VERSION 5.7 ;
  NOWIREEXTENSIONATPIN ON ;
  DIVIDERCHAR "/" ;
  BUSBITCHARS "[]" ;
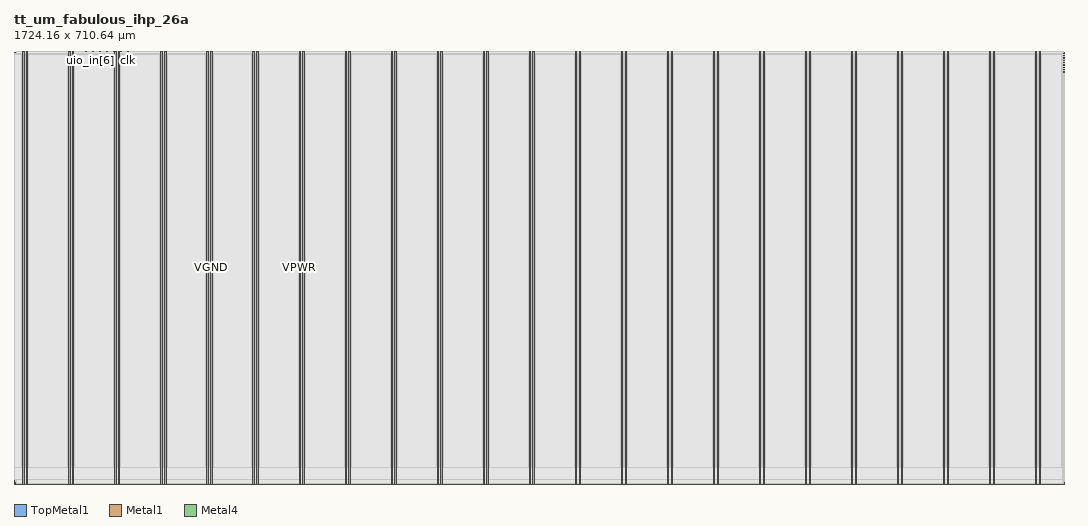
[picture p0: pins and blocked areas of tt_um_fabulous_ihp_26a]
MACRO tt_um_fabulous_ihp_26a
  CLASS BLOCK ;
  FOREIGN tt_um_fabulous_ihp_26a ;
  ORIGIN 0.000 0.000 ;
  SIZE 1724.160 BY 710.640 ;
  PIN VGND
    DIRECTION INOUT ;
    USE GROUND ;
    PORT
      LAYER TopMetal1 ;
        RECT 20.620 0.000 22.820 710.640 ;
    END
    PORT
      LAYER TopMetal1 ;
        RECT 96.220 0.000 98.420 710.640 ;
    END
    PORT
      LAYER TopMetal1 ;
        RECT 171.820 0.000 174.020 710.640 ;
    END
    PORT
      LAYER TopMetal1 ;
        RECT 247.420 0.000 249.620 710.640 ;
    END
    PORT
      LAYER TopMetal1 ;
        RECT 323.020 0.000 325.220 710.640 ;
    END
    PORT
      LAYER TopMetal1 ;
        RECT 398.620 0.000 400.820 710.640 ;
    END
    PORT
      LAYER TopMetal1 ;
        RECT 474.220 0.000 476.420 710.640 ;
    END
    PORT
      LAYER TopMetal1 ;
        RECT 549.820 0.000 552.020 710.640 ;
    END
    PORT
      LAYER TopMetal1 ;
        RECT 625.420 0.000 627.620 710.640 ;
    END
    PORT
      LAYER TopMetal1 ;
        RECT 701.020 0.000 703.220 710.640 ;
    END
    PORT
      LAYER TopMetal1 ;
        RECT 776.620 0.000 778.820 710.640 ;
    END
    PORT
      LAYER TopMetal1 ;
        RECT 852.220 0.000 854.420 710.640 ;
    END
    PORT
      LAYER TopMetal1 ;
        RECT 927.820 0.000 930.020 710.640 ;
    END
    PORT
      LAYER TopMetal1 ;
        RECT 1003.420 0.000 1005.620 710.640 ;
    END
    PORT
      LAYER TopMetal1 ;
        RECT 1079.020 0.000 1081.220 710.640 ;
    END
    PORT
      LAYER TopMetal1 ;
        RECT 1154.620 0.000 1156.820 710.640 ;
    END
    PORT
      LAYER TopMetal1 ;
        RECT 1230.220 0.000 1232.420 710.640 ;
    END
    PORT
      LAYER TopMetal1 ;
        RECT 1305.820 0.000 1308.020 710.640 ;
    END
    PORT
      LAYER TopMetal1 ;
        RECT 1381.420 0.000 1383.620 710.640 ;
    END
    PORT
      LAYER TopMetal1 ;
        RECT 1457.020 0.000 1459.220 710.640 ;
    END
    PORT
      LAYER TopMetal1 ;
        RECT 1532.620 0.000 1534.820 710.640 ;
    END
    PORT
      LAYER TopMetal1 ;
        RECT 1608.220 0.000 1610.420 710.640 ;
    END
    PORT
      LAYER TopMetal1 ;
        RECT 1683.820 0.000 1686.020 710.640 ;
    END
    PORT
      LAYER Metal1 ;
        RECT 1724.000 680.180 1724.160 680.620 ;
    END
    PORT
      LAYER Metal1 ;
        RECT 1724.000 687.740 1724.160 688.180 ;
    END
    PORT
      LAYER Metal1 ;
        RECT 1724.000 695.300 1724.160 695.740 ;
    END
    PORT
      LAYER Metal1 ;
        RECT 1724.000 702.860 1724.160 703.300 ;
    END
  END VGND
  PIN VPWR
    DIRECTION INOUT ;
    USE POWER ;
    PORT
      LAYER TopMetal1 ;
        RECT 14.420 0.000 16.620 710.640 ;
    END
    PORT
      LAYER TopMetal1 ;
        RECT 90.020 0.000 92.220 710.640 ;
    END
    PORT
      LAYER TopMetal1 ;
        RECT 165.620 0.000 167.820 710.640 ;
    END
    PORT
      LAYER TopMetal1 ;
        RECT 241.220 0.000 243.420 710.640 ;
    END
    PORT
      LAYER TopMetal1 ;
        RECT 316.820 0.000 319.020 710.640 ;
    END
    PORT
      LAYER TopMetal1 ;
        RECT 392.420 0.000 394.620 710.640 ;
    END
    PORT
      LAYER TopMetal1 ;
        RECT 468.020 0.000 470.220 710.640 ;
    END
    PORT
      LAYER TopMetal1 ;
        RECT 543.620 0.000 545.820 710.640 ;
    END
    PORT
      LAYER TopMetal1 ;
        RECT 619.220 0.000 621.420 710.640 ;
    END
    PORT
      LAYER TopMetal1 ;
        RECT 694.820 0.000 697.020 710.640 ;
    END
    PORT
      LAYER TopMetal1 ;
        RECT 770.420 0.000 772.620 710.640 ;
    END
    PORT
      LAYER TopMetal1 ;
        RECT 846.020 0.000 848.220 710.640 ;
    END
    PORT
      LAYER TopMetal1 ;
        RECT 921.620 0.000 923.820 710.640 ;
    END
    PORT
      LAYER TopMetal1 ;
        RECT 997.220 0.000 999.420 710.640 ;
    END
    PORT
      LAYER TopMetal1 ;
        RECT 1072.820 0.000 1075.020 710.640 ;
    END
    PORT
      LAYER TopMetal1 ;
        RECT 1148.420 0.000 1150.620 710.640 ;
    END
    PORT
      LAYER TopMetal1 ;
        RECT 1224.020 0.000 1226.220 710.640 ;
    END
    PORT
      LAYER TopMetal1 ;
        RECT 1299.620 0.000 1301.820 710.640 ;
    END
    PORT
      LAYER TopMetal1 ;
        RECT 1375.220 0.000 1377.420 710.640 ;
    END
    PORT
      LAYER TopMetal1 ;
        RECT 1450.820 0.000 1453.020 710.640 ;
    END
    PORT
      LAYER TopMetal1 ;
        RECT 1526.420 0.000 1528.620 710.640 ;
    END
    PORT
      LAYER TopMetal1 ;
        RECT 1602.020 0.000 1604.220 710.640 ;
    END
    PORT
      LAYER TopMetal1 ;
        RECT 1677.620 0.000 1679.820 710.640 ;
    END
    PORT
      LAYER Metal1 ;
        RECT 1724.000 676.400 1724.160 676.840 ;
    END
    PORT
      LAYER Metal1 ;
        RECT 1724.000 683.960 1724.160 684.400 ;
    END
    PORT
      LAYER Metal1 ;
        RECT 1724.000 691.520 1724.160 691.960 ;
    END
    PORT
      LAYER Metal1 ;
        RECT 1724.000 699.080 1724.160 699.520 ;
    END
    PORT
      LAYER Metal1 ;
        RECT 1724.000 706.640 1724.160 707.080 ;
    END
  END VPWR
  PIN clk
    DIRECTION INPUT ;
    USE SIGNAL ;
    ANTENNAGATEAREA 2.901600 ;
    PORT
      LAYER Metal4 ;
        RECT 187.050 709.640 187.350 710.640 ;
    END
  END clk
  PIN ena
    DIRECTION INPUT ;
    USE SIGNAL ;
    PORT
      LAYER Metal4 ;
        RECT 190.890 709.640 191.190 710.640 ;
    END
  END ena
  PIN rst_n
    DIRECTION INPUT ;
    USE SIGNAL ;
    ANTENNAGATEAREA 0.180700 ;
    PORT
      LAYER Metal4 ;
        RECT 183.210 709.640 183.510 710.640 ;
    END
  END rst_n
  PIN ui_in[0]
    DIRECTION INPUT ;
    USE SIGNAL ;
    ANTENNAGATEAREA 0.180700 ;
    PORT
      LAYER Metal4 ;
        RECT 179.370 709.640 179.670 710.640 ;
    END
  END ui_in[0]
  PIN ui_in[1]
    DIRECTION INPUT ;
    USE SIGNAL ;
    ANTENNAGATEAREA 0.180700 ;
    PORT
      LAYER Metal4 ;
        RECT 175.530 709.640 175.830 710.640 ;
    END
  END ui_in[1]
  PIN ui_in[2]
    DIRECTION INPUT ;
    USE SIGNAL ;
    ANTENNAGATEAREA 0.335400 ;
    PORT
      LAYER Metal4 ;
        RECT 171.690 709.640 171.990 710.640 ;
    END
  END ui_in[2]
  PIN ui_in[3]
    DIRECTION INPUT ;
    USE SIGNAL ;
    ANTENNAGATEAREA 0.335400 ;
    PORT
      LAYER Metal4 ;
        RECT 167.850 709.640 168.150 710.640 ;
    END
  END ui_in[3]
  PIN ui_in[4]
    DIRECTION INPUT ;
    USE SIGNAL ;
    ANTENNAGATEAREA 0.335400 ;
    ANTENNADIFFAREA 4.030800 ;
    PORT
      LAYER Metal4 ;
        RECT 164.010 709.640 164.310 710.640 ;
    END
  END ui_in[4]
  PIN ui_in[5]
    DIRECTION INPUT ;
    USE SIGNAL ;
    ANTENNAGATEAREA 0.335400 ;
    ANTENNADIFFAREA 6.046200 ;
    PORT
      LAYER Metal4 ;
        RECT 160.170 709.640 160.470 710.640 ;
    END
  END ui_in[5]
  PIN ui_in[6]
    DIRECTION INPUT ;
    USE SIGNAL ;
    ANTENNAGATEAREA 0.335400 ;
    ANTENNADIFFAREA 2.015400 ;
    PORT
      LAYER Metal4 ;
        RECT 156.330 709.640 156.630 710.640 ;
    END
  END ui_in[6]
  PIN ui_in[7]
    DIRECTION INPUT ;
    USE SIGNAL ;
    ANTENNAGATEAREA 0.335400 ;
    ANTENNADIFFAREA 2.015400 ;
    PORT
      LAYER Metal4 ;
        RECT 152.490 709.640 152.790 710.640 ;
    END
  END ui_in[7]
  PIN uio_in[0]
    DIRECTION INPUT ;
    USE SIGNAL ;
    ANTENNAGATEAREA 0.335400 ;
    PORT
      LAYER Metal4 ;
        RECT 148.650 709.640 148.950 710.640 ;
    END
  END uio_in[0]
  PIN uio_in[1]
    DIRECTION INPUT ;
    USE SIGNAL ;
    ANTENNAGATEAREA 0.335400 ;
    PORT
      LAYER Metal4 ;
        RECT 144.810 709.640 145.110 710.640 ;
    END
  END uio_in[1]
  PIN uio_in[2]
    DIRECTION INPUT ;
    USE SIGNAL ;
    ANTENNAGATEAREA 0.289900 ;
    PORT
      LAYER Metal4 ;
        RECT 140.970 709.640 141.270 710.640 ;
    END
  END uio_in[2]
  PIN uio_in[3]
    DIRECTION INPUT ;
    USE SIGNAL ;
    ANTENNAGATEAREA 0.289900 ;
    PORT
      LAYER Metal4 ;
        RECT 137.130 709.640 137.430 710.640 ;
    END
  END uio_in[3]
  PIN uio_in[4]
    DIRECTION INPUT ;
    USE SIGNAL ;
    ANTENNAGATEAREA 0.335400 ;
    ANTENNADIFFAREA 2.015400 ;
    PORT
      LAYER Metal4 ;
        RECT 133.290 709.640 133.590 710.640 ;
    END
  END uio_in[4]
  PIN uio_in[5]
    DIRECTION INPUT ;
    USE SIGNAL ;
    ANTENNAGATEAREA 0.335400 ;
    PORT
      LAYER Metal4 ;
        RECT 129.450 709.640 129.750 710.640 ;
    END
  END uio_in[5]
  PIN uio_in[6]
    DIRECTION INPUT ;
    USE SIGNAL ;
    ANTENNAGATEAREA 0.289900 ;
    ANTENNADIFFAREA 2.015400 ;
    PORT
      LAYER Metal4 ;
        RECT 125.610 709.640 125.910 710.640 ;
    END
  END uio_in[6]
  PIN uio_in[7]
    DIRECTION INPUT ;
    USE SIGNAL ;
    ANTENNAGATEAREA 0.289900 ;
    ANTENNADIFFAREA 2.015400 ;
    PORT
      LAYER Metal4 ;
        RECT 121.770 709.640 122.070 710.640 ;
    END
  END uio_in[7]
  PIN uio_oe[0]
    DIRECTION OUTPUT ;
    USE SIGNAL ;
    ANTENNADIFFAREA 0.708600 ;
    PORT
      LAYER Metal4 ;
        RECT 56.490 709.640 56.790 710.640 ;
    END
  END uio_oe[0]
  PIN uio_oe[1]
    DIRECTION OUTPUT ;
    USE SIGNAL ;
    ANTENNADIFFAREA 0.708600 ;
    PORT
      LAYER Metal4 ;
        RECT 52.650 709.640 52.950 710.640 ;
    END
  END uio_oe[1]
  PIN uio_oe[2]
    DIRECTION OUTPUT ;
    USE SIGNAL ;
    ANTENNADIFFAREA 0.708600 ;
    PORT
      LAYER Metal4 ;
        RECT 48.810 709.640 49.110 710.640 ;
    END
  END uio_oe[2]
  PIN uio_oe[3]
    DIRECTION OUTPUT ;
    USE SIGNAL ;
    ANTENNADIFFAREA 0.708600 ;
    PORT
      LAYER Metal4 ;
        RECT 44.970 709.640 45.270 710.640 ;
    END
  END uio_oe[3]
  PIN uio_oe[4]
    DIRECTION OUTPUT ;
    USE SIGNAL ;
    ANTENNADIFFAREA 0.708600 ;
    PORT
      LAYER Metal4 ;
        RECT 41.130 709.640 41.430 710.640 ;
    END
  END uio_oe[4]
  PIN uio_oe[5]
    DIRECTION OUTPUT ;
    USE SIGNAL ;
    ANTENNADIFFAREA 0.708600 ;
    PORT
      LAYER Metal4 ;
        RECT 37.290 709.640 37.590 710.640 ;
    END
  END uio_oe[5]
  PIN uio_oe[6]
    DIRECTION OUTPUT ;
    USE SIGNAL ;
    ANTENNADIFFAREA 0.708600 ;
    PORT
      LAYER Metal4 ;
        RECT 33.450 709.640 33.750 710.640 ;
    END
  END uio_oe[6]
  PIN uio_oe[7]
    DIRECTION OUTPUT ;
    USE SIGNAL ;
    ANTENNADIFFAREA 0.708600 ;
    PORT
      LAYER Metal4 ;
        RECT 29.610 709.640 29.910 710.640 ;
    END
  END uio_oe[7]
  PIN uio_out[0]
    DIRECTION OUTPUT ;
    USE SIGNAL ;
    ANTENNADIFFAREA 0.708600 ;
    PORT
      LAYER Metal4 ;
        RECT 87.210 709.640 87.510 710.640 ;
    END
  END uio_out[0]
  PIN uio_out[1]
    DIRECTION OUTPUT ;
    USE SIGNAL ;
    ANTENNADIFFAREA 0.708600 ;
    PORT
      LAYER Metal4 ;
        RECT 83.370 709.640 83.670 710.640 ;
    END
  END uio_out[1]
  PIN uio_out[2]
    DIRECTION OUTPUT ;
    USE SIGNAL ;
    ANTENNADIFFAREA 0.708600 ;
    PORT
      LAYER Metal4 ;
        RECT 79.530 709.640 79.830 710.640 ;
    END
  END uio_out[2]
  PIN uio_out[3]
    DIRECTION OUTPUT ;
    USE SIGNAL ;
    ANTENNADIFFAREA 0.708600 ;
    PORT
      LAYER Metal4 ;
        RECT 75.690 709.640 75.990 710.640 ;
    END
  END uio_out[3]
  PIN uio_out[4]
    DIRECTION OUTPUT ;
    USE SIGNAL ;
    ANTENNADIFFAREA 0.708600 ;
    PORT
      LAYER Metal4 ;
        RECT 71.850 709.640 72.150 710.640 ;
    END
  END uio_out[4]
  PIN uio_out[5]
    DIRECTION OUTPUT ;
    USE SIGNAL ;
    ANTENNADIFFAREA 0.708600 ;
    PORT
      LAYER Metal4 ;
        RECT 68.010 709.640 68.310 710.640 ;
    END
  END uio_out[5]
  PIN uio_out[6]
    DIRECTION OUTPUT ;
    USE SIGNAL ;
    ANTENNADIFFAREA 0.708600 ;
    PORT
      LAYER Metal4 ;
        RECT 64.170 709.640 64.470 710.640 ;
    END
  END uio_out[6]
  PIN uio_out[7]
    DIRECTION OUTPUT ;
    USE SIGNAL ;
    ANTENNADIFFAREA 0.708600 ;
    PORT
      LAYER Metal4 ;
        RECT 60.330 709.640 60.630 710.640 ;
    END
  END uio_out[7]
  PIN uo_out[0]
    DIRECTION OUTPUT ;
    USE SIGNAL ;
    ANTENNADIFFAREA 0.708600 ;
    PORT
      LAYER Metal4 ;
        RECT 117.930 709.640 118.230 710.640 ;
    END
  END uo_out[0]
  PIN uo_out[1]
    DIRECTION OUTPUT ;
    USE SIGNAL ;
    ANTENNADIFFAREA 0.708600 ;
    PORT
      LAYER Metal4 ;
        RECT 114.090 709.640 114.390 710.640 ;
    END
  END uo_out[1]
  PIN uo_out[2]
    DIRECTION OUTPUT ;
    USE SIGNAL ;
    ANTENNADIFFAREA 0.708600 ;
    PORT
      LAYER Metal4 ;
        RECT 110.250 709.640 110.550 710.640 ;
    END
  END uo_out[2]
  PIN uo_out[3]
    DIRECTION OUTPUT ;
    USE SIGNAL ;
    ANTENNADIFFAREA 0.708600 ;
    PORT
      LAYER Metal4 ;
        RECT 106.410 709.640 106.710 710.640 ;
    END
  END uo_out[3]
  PIN uo_out[4]
    DIRECTION OUTPUT ;
    USE SIGNAL ;
    ANTENNADIFFAREA 0.708600 ;
    PORT
      LAYER Metal4 ;
        RECT 102.570 709.640 102.870 710.640 ;
    END
  END uo_out[4]
  PIN uo_out[5]
    DIRECTION OUTPUT ;
    USE SIGNAL ;
    ANTENNADIFFAREA 0.708600 ;
    PORT
      LAYER Metal4 ;
        RECT 98.730 709.640 99.030 710.640 ;
    END
  END uo_out[5]
  PIN uo_out[6]
    DIRECTION OUTPUT ;
    USE SIGNAL ;
    ANTENNADIFFAREA 0.708600 ;
    PORT
      LAYER Metal4 ;
        RECT 94.890 709.640 95.190 710.640 ;
    END
  END uo_out[6]
  PIN uo_out[7]
    DIRECTION OUTPUT ;
    USE SIGNAL ;
    ANTENNADIFFAREA 0.708600 ;
    PORT
      LAYER Metal4 ;
        RECT 91.050 709.640 91.350 710.640 ;
    END
  END uo_out[7]
  OBS
      LAYER GatPoly ;
        RECT 1.920 4.050 1724.160 707.010 ;
      LAYER Metal1 ;
        RECT 1.920 706.460 1723.820 707.080 ;
        RECT 1.920 703.480 1724.030 706.460 ;
        RECT 1.920 702.680 1723.820 703.480 ;
        RECT 1.920 699.700 1724.030 702.680 ;
        RECT 1.920 698.900 1723.820 699.700 ;
        RECT 1.920 695.920 1724.030 698.900 ;
        RECT 1.920 695.120 1723.820 695.920 ;
        RECT 1.920 692.140 1724.030 695.120 ;
        RECT 1.920 691.340 1723.820 692.140 ;
        RECT 1.920 688.360 1724.030 691.340 ;
        RECT 1.920 687.560 1723.820 688.360 ;
        RECT 1.920 684.580 1724.030 687.560 ;
        RECT 1.920 683.780 1723.820 684.580 ;
        RECT 1.920 680.800 1724.030 683.780 ;
        RECT 1.920 680.000 1723.820 680.800 ;
        RECT 1.920 677.020 1724.030 680.000 ;
        RECT 1.920 676.220 1723.820 677.020 ;
        RECT 1.920 3.980 1724.030 676.220 ;
      LAYER Metal2 ;
        RECT 3.735 0.420 1723.785 709.105 ;
      LAYER Metal3 ;
        RECT 3.695 2.740 1723.825 709.485 ;
      LAYER Metal4 ;
        RECT 4.695 709.430 29.400 709.640 ;
        RECT 30.120 709.430 33.240 709.640 ;
        RECT 33.960 709.430 37.080 709.640 ;
        RECT 37.800 709.430 40.920 709.640 ;
        RECT 41.640 709.430 44.760 709.640 ;
        RECT 45.480 709.430 48.600 709.640 ;
        RECT 49.320 709.430 52.440 709.640 ;
        RECT 53.160 709.430 56.280 709.640 ;
        RECT 57.000 709.430 60.120 709.640 ;
        RECT 60.840 709.430 63.960 709.640 ;
        RECT 64.680 709.430 67.800 709.640 ;
        RECT 68.520 709.430 71.640 709.640 ;
        RECT 72.360 709.430 75.480 709.640 ;
        RECT 76.200 709.430 79.320 709.640 ;
        RECT 80.040 709.430 83.160 709.640 ;
        RECT 83.880 709.430 87.000 709.640 ;
        RECT 87.720 709.430 90.840 709.640 ;
        RECT 91.560 709.430 94.680 709.640 ;
        RECT 95.400 709.430 98.520 709.640 ;
        RECT 99.240 709.430 102.360 709.640 ;
        RECT 103.080 709.430 106.200 709.640 ;
        RECT 106.920 709.430 110.040 709.640 ;
        RECT 110.760 709.430 113.880 709.640 ;
        RECT 114.600 709.430 117.720 709.640 ;
        RECT 118.440 709.430 121.560 709.640 ;
        RECT 122.280 709.430 125.400 709.640 ;
        RECT 126.120 709.430 129.240 709.640 ;
        RECT 129.960 709.430 133.080 709.640 ;
        RECT 133.800 709.430 136.920 709.640 ;
        RECT 137.640 709.430 140.760 709.640 ;
        RECT 141.480 709.430 144.600 709.640 ;
        RECT 145.320 709.430 148.440 709.640 ;
        RECT 149.160 709.430 152.280 709.640 ;
        RECT 153.000 709.430 156.120 709.640 ;
        RECT 156.840 709.430 159.960 709.640 ;
        RECT 160.680 709.430 163.800 709.640 ;
        RECT 164.520 709.430 167.640 709.640 ;
        RECT 168.360 709.430 171.480 709.640 ;
        RECT 172.200 709.430 175.320 709.640 ;
        RECT 176.040 709.430 179.160 709.640 ;
        RECT 179.880 709.430 183.000 709.640 ;
        RECT 183.720 709.430 186.840 709.640 ;
        RECT 187.560 709.430 190.680 709.640 ;
        RECT 191.400 709.430 1720.905 709.640 ;
        RECT 4.695 0.420 1720.905 709.430 ;
      LAYER Metal5 ;
        RECT 1.330 7.250 1720.945 707.170 ;
      LAYER TopMetal1 ;
        RECT 0.820 27.740 12.780 706.000 ;
        RECT 18.260 27.740 18.980 706.000 ;
        RECT 24.460 27.740 88.380 706.000 ;
        RECT 93.860 27.740 94.580 706.000 ;
        RECT 100.060 27.740 163.980 706.000 ;
        RECT 169.460 27.740 170.180 706.000 ;
        RECT 175.660 27.740 239.580 706.000 ;
        RECT 245.060 27.740 245.780 706.000 ;
        RECT 251.260 27.740 315.180 706.000 ;
        RECT 320.660 27.740 321.380 706.000 ;
        RECT 326.860 27.740 390.780 706.000 ;
        RECT 396.260 27.740 396.980 706.000 ;
        RECT 402.460 27.740 466.380 706.000 ;
        RECT 471.860 27.740 472.580 706.000 ;
        RECT 478.060 27.740 541.980 706.000 ;
        RECT 547.460 27.740 548.180 706.000 ;
        RECT 553.660 27.740 617.580 706.000 ;
        RECT 623.060 27.740 623.780 706.000 ;
        RECT 629.260 27.740 693.180 706.000 ;
        RECT 698.660 27.740 699.380 706.000 ;
        RECT 704.860 27.740 768.780 706.000 ;
        RECT 774.260 27.740 774.980 706.000 ;
        RECT 780.460 27.740 844.380 706.000 ;
        RECT 849.860 27.740 850.580 706.000 ;
        RECT 856.060 27.740 919.980 706.000 ;
        RECT 925.460 27.740 926.180 706.000 ;
        RECT 931.660 27.740 995.580 706.000 ;
        RECT 1001.060 27.740 1001.780 706.000 ;
        RECT 1007.260 27.740 1071.180 706.000 ;
        RECT 1076.660 27.740 1077.380 706.000 ;
        RECT 1082.860 27.740 1146.780 706.000 ;
        RECT 1152.260 27.740 1152.980 706.000 ;
        RECT 1158.460 27.740 1222.380 706.000 ;
        RECT 1227.860 27.740 1228.580 706.000 ;
        RECT 1234.060 27.740 1297.980 706.000 ;
        RECT 1303.460 27.740 1304.180 706.000 ;
        RECT 1309.660 27.740 1373.580 706.000 ;
        RECT 1379.060 27.740 1379.780 706.000 ;
        RECT 1385.260 27.740 1449.180 706.000 ;
        RECT 1454.660 27.740 1455.380 706.000 ;
        RECT 1460.860 27.740 1524.780 706.000 ;
        RECT 1530.260 27.740 1530.980 706.000 ;
        RECT 1536.460 27.740 1600.380 706.000 ;
        RECT 1605.860 27.740 1606.580 706.000 ;
        RECT 1612.060 27.740 1675.980 706.000 ;
        RECT 1681.460 27.740 1682.180 706.000 ;
        RECT 1687.660 27.740 1719.300 706.000 ;
  END
END tt_um_fabulous_ihp_26a
END LIBRARY

